VERSION 5.8 ;
BUSBITCHARS "[]" ;
DIVIDERCHAR "/" ;

# R1 pad ring reference abstract (empty core). Units um. Pins: bondpad TopMetal2 squares (70 x 70 um).
# Core window and ring: see README. Obstructions: core power ring (TopMetal1 / TopMetal2).

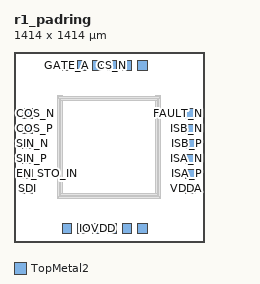
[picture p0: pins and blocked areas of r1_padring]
MACRO r1_padring
  CLASS BLOCK ;
  ORIGIN 0 0 ;
  FOREIGN r1_padring 0 0 ;
  SIZE 1414 BY 1414 ;
  SYMMETRY X Y ;
  PIN VDD
    DIRECTION INOUT ;
    USE POWER ;
    PORT
      LAYER TopMetal2 ;
        RECT 360.000 66.000 430.000 136.000 ;
    END
  END VDD
  PIN VSS
    DIRECTION INOUT ;
    USE GROUND ;
    PORT
      LAYER TopMetal2 ;
        RECT 472.000 66.000 542.000 136.000 ;
        RECT 808.000 66.000 878.000 136.000 ;
    END
  END VSS
  PIN IOVDD
    DIRECTION INOUT ;
    USE POWER ;
    PORT
      LAYER TopMetal2 ;
        RECT 584.000 66.000 654.000 136.000 ;
    END
  END IOVDD
  PIN IOVSS
    DIRECTION INOUT ;
    USE GROUND ;
    PORT
      LAYER TopMetal2 ;
        RECT 696.000 66.000 766.000 136.000 ;
        RECT 920.000 66.000 990.000 136.000 ;
    END
  END IOVSS
  PIN VDDA
    DIRECTION INOUT ;
    USE POWER ;
    PORT
      LAYER TopMetal2 ;
        RECT 1278.000 360.000 1348.000 430.000 ;
    END
  END VDDA
  PIN ISA_P
    DIRECTION INOUT ;
    USE SIGNAL ;
    PORT
      LAYER TopMetal2 ;
        RECT 1278.000 472.000 1348.000 542.000 ;
    END
  END ISA_P
  PIN ISA_N
    DIRECTION INOUT ;
    USE SIGNAL ;
    PORT
      LAYER TopMetal2 ;
        RECT 1278.000 584.000 1348.000 654.000 ;
    END
  END ISA_N
  PIN ISB_P
    DIRECTION INOUT ;
    USE SIGNAL ;
    PORT
      LAYER TopMetal2 ;
        RECT 1278.000 696.000 1348.000 766.000 ;
    END
  END ISB_P
  PIN ISB_N
    DIRECTION INOUT ;
    USE SIGNAL ;
    PORT
      LAYER TopMetal2 ;
        RECT 1278.000 808.000 1348.000 878.000 ;
    END
  END ISB_N
  PIN FAULT_N
    DIRECTION INOUT ;
    USE SIGNAL ;
    PORT
      LAYER TopMetal2 ;
        RECT 1278.000 920.000 1348.000 990.000 ;
    END
  END FAULT_N
  PIN GATE_A
    DIRECTION INOUT ;
    USE SIGNAL ;
    PORT
      LAYER TopMetal2 ;
        RECT 360.000 1278.000 430.000 1348.000 ;
    END
  END GATE_A
  PIN GATE_B
    DIRECTION INOUT ;
    USE SIGNAL ;
    PORT
      LAYER TopMetal2 ;
        RECT 472.000 1278.000 542.000 1348.000 ;
    END
  END GATE_B
  PIN GATE_C
    DIRECTION INOUT ;
    USE SIGNAL ;
    PORT
      LAYER TopMetal2 ;
        RECT 584.000 1278.000 654.000 1348.000 ;
    END
  END GATE_C
  PIN CS_N
    DIRECTION INOUT ;
    USE SIGNAL ;
    PORT
      LAYER TopMetal2 ;
        RECT 696.000 1278.000 766.000 1348.000 ;
    END
  END CS_N
  PIN MA_SCLK
    DIRECTION INOUT ;
    USE SIGNAL ;
    PORT
      LAYER TopMetal2 ;
        RECT 808.000 1278.000 878.000 1348.000 ;
    END
  END MA_SCLK
  PIN SLO_SDO
    DIRECTION INOUT ;
    USE SIGNAL ;
    PORT
      LAYER TopMetal2 ;
        RECT 920.000 1278.000 990.000 1348.000 ;
    END
  END SLO_SDO
  PIN SDI
    DIRECTION INOUT ;
    USE SIGNAL ;
    PORT
      LAYER TopMetal2 ;
        RECT 66.000 360.000 136.000 430.000 ;
    END
  END SDI
  PIN EN_STO_IN
    DIRECTION INOUT ;
    USE SIGNAL ;
    PORT
      LAYER TopMetal2 ;
        RECT 66.000 472.000 136.000 542.000 ;
    END
  END EN_STO_IN
  PIN SIN_P
    DIRECTION INOUT ;
    USE SIGNAL ;
    PORT
      LAYER TopMetal2 ;
        RECT 66.000 584.000 136.000 654.000 ;
    END
  END SIN_P
  PIN SIN_N
    DIRECTION INOUT ;
    USE SIGNAL ;
    PORT
      LAYER TopMetal2 ;
        RECT 66.000 696.000 136.000 766.000 ;
    END
  END SIN_N
  PIN COS_P
    DIRECTION INOUT ;
    USE SIGNAL ;
    PORT
      LAYER TopMetal2 ;
        RECT 66.000 808.000 136.000 878.000 ;
    END
  END COS_P
  PIN COS_N
    DIRECTION INOUT ;
    USE SIGNAL ;
    PORT
      LAYER TopMetal2 ;
        RECT 66.000 920.000 136.000 990.000 ;
    END
  END COS_N
  OBS
    LAYER TopMetal1 ;
      RECT 324.820 321.000 339.820 1093.000 ;
      RECT 344.820 321.000 361.800 1093.000 ;
      RECT 1054.420 321.000 1069.420 1093.000 ;
      RECT 1074.420 321.000 1089.420 1093.000 ;
      RECT 1054.420 347.160 1069.420 1066.300 ;
      RECT 344.820 347.160 359.820 1066.300 ;
      RECT 1074.420 327.160 1089.420 1086.300 ;
      RECT 324.820 327.160 339.820 1086.300 ;
    LAYER TopMetal2 ;
      RECT 344.820 1051.300 1069.420 1066.300 ;
      RECT 344.820 347.160 1069.420 362.160 ;
      RECT 328.000 1071.300 1086.000 1086.300 ;
      RECT 328.000 327.160 1086.000 342.160 ;
  END
END r1_padring

END LIBRARY
